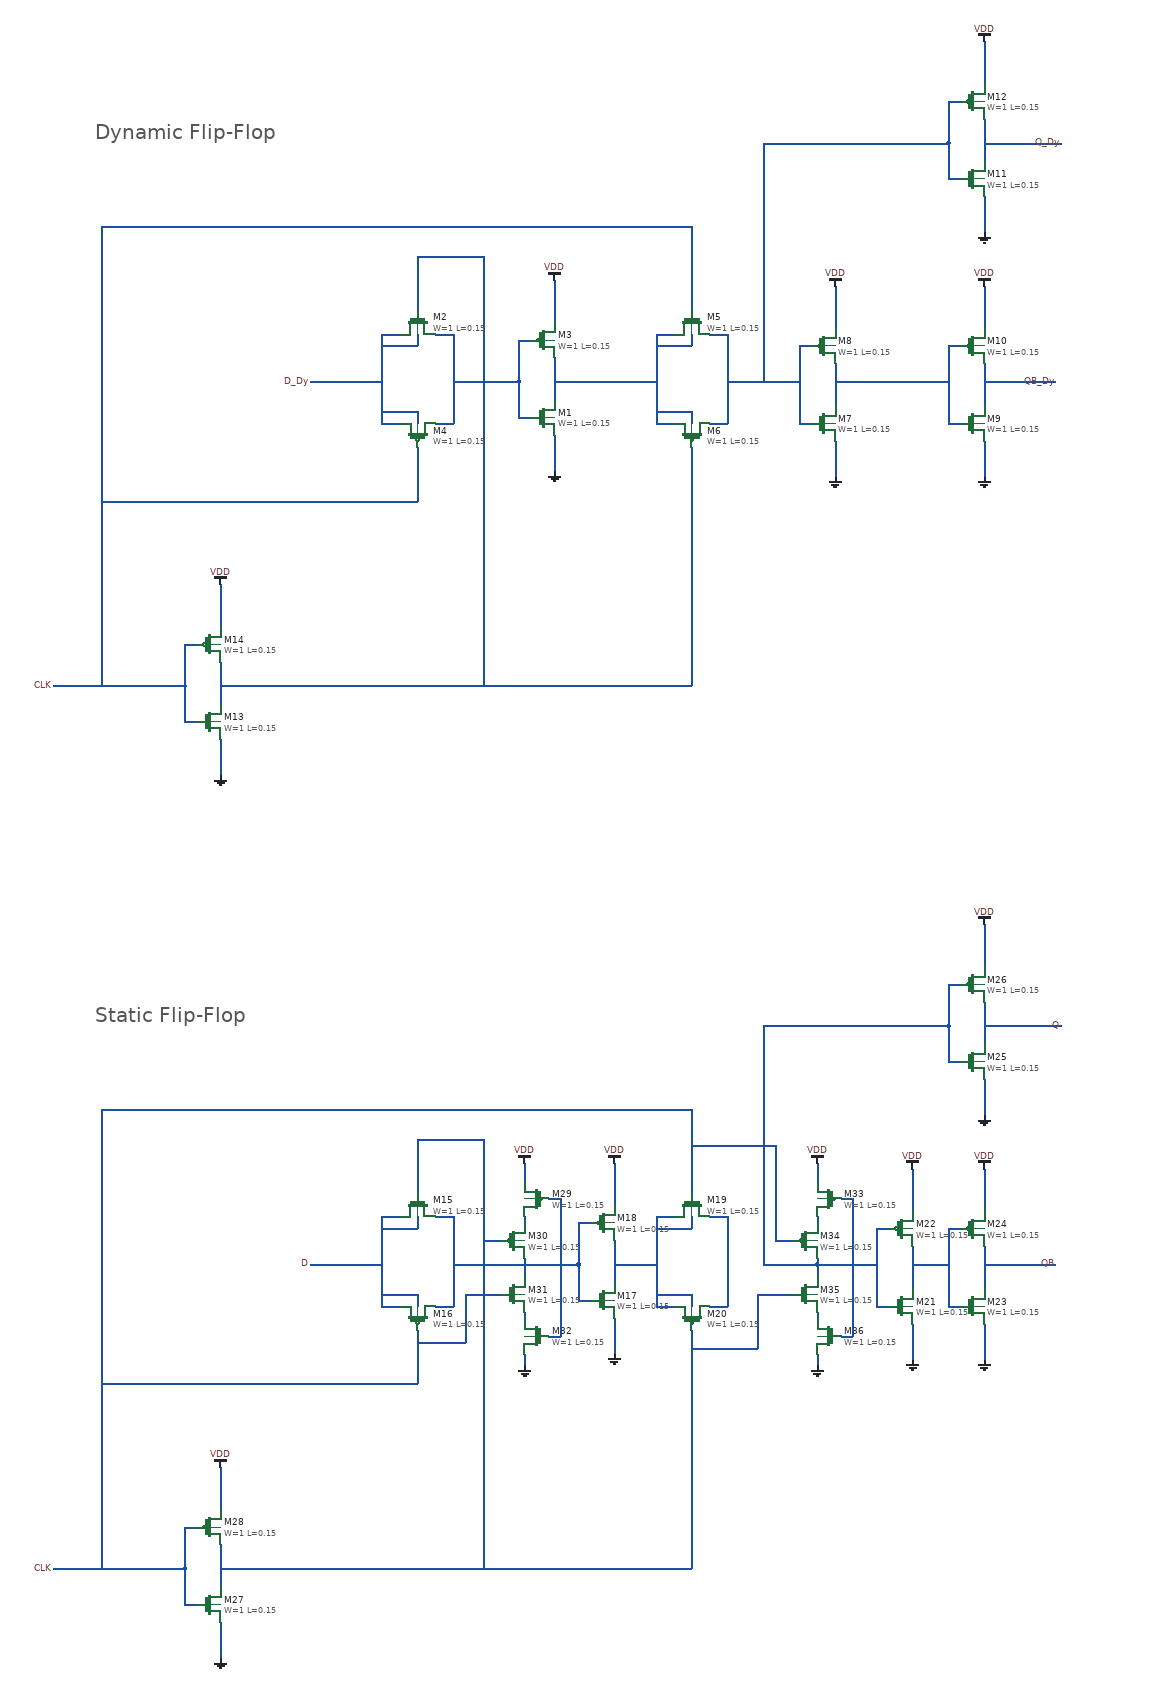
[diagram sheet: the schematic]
v {xschem version=3.4.5 file_version=1.2
}
G {}
K {}
V {}
S {}
E {}
T {Dynamic Flip-Flop
} -1080 -430 0 0 1 1 {}
T {Static Flip-Flop
} -1080 1050 0 0 1 1 {}
N -600 -80 -570 -80 {
lab=D_Dy}
N -600 70 -570 70 {
lab=D_Dy}
N -600 -80 -600 70 {
lab=D_Dy}
N -510 -80 -480 -80 {
lab=#net1}
N -480 -80 -480 70 {
lab=#net1}
N -510 70 -480 70 {
lab=#net1}
N -480 -0 -370 0 {
lab=#net1}
N -540 -80 -540 -60 {
lab=D_Dy}
N -600 -60 -540 -60 {
lab=D_Dy}
N -540 50 -540 70 {
lab=D_Dy}
N -600 50 -540 50 {
lab=D_Dy}
N -310 -40 -310 30 {
lab=#net2}
N -370 -70 -370 0 {
lab=#net1}
N -370 -70 -350 -70 {
lab=#net1}
N -370 -0 -370 60 {
lab=#net1}
N -370 60 -350 60 {
lab=#net1}
N -310 90 -310 150 {
lab=GND}
N -310 -170 -310 -100 {
lab=VDD}
N -140 -80 -110 -80 {
lab=#net2}
N -140 70 -110 70 {
lab=#net2}
N -140 -80 -140 70 {
lab=#net2}
N -50 -80 -20 -80 {
lab=#net3}
N -20 -80 -20 70 {
lab=#net3}
N -50 70 -20 70 {
lab=#net3}
N -80 -80 -80 -60 {
lab=#net2}
N -140 -60 -80 -60 {
lab=#net2}
N -80 50 -80 70 {
lab=#net2}
N -140 50 -80 50 {
lab=#net2}
N -310 0 -140 0 {
lab=#net2}
N 160 -30 160 40 {
lab=#net4}
N 100 -60 100 10 {
lab=#net3}
N 100 -60 120 -60 {
lab=#net3}
N 100 10 100 70 {
lab=#net3}
N 100 70 120 70 {
lab=#net3}
N 160 100 160 160 {
lab=GND}
N 160 -160 160 -90 {
lab=VDD}
N -20 0 100 -0 {
lab=#net3}
N 410 -30 410 40 {
lab=QB_Dy}
N 350 -60 350 10 {
lab=#net4}
N 350 -60 370 -60 {
lab=#net4}
N 350 10 350 70 {
lab=#net4}
N 350 70 370 70 {
lab=#net4}
N 410 100 410 160 {
lab=GND}
N 410 -160 410 -90 {
lab=VDD}
N 410 -440 410 -370 {
lab=Q_Dy}
N 350 -470 350 -400 {
lab=#net3}
N 350 -470 370 -470 {
lab=#net3}
N 350 -400 350 -340 {
lab=#net3}
N 350 -340 370 -340 {
lab=#net3}
N 410 -310 410 -250 {
lab=GND}
N 410 -570 410 -500 {
lab=VDD}
N 160 0 350 0 {
lab=#net4}
N 40 -400 350 -400 {
lab=#net3}
N 40 -400 40 0 {
lab=#net3}
N 410 -400 540 -400 {
lab=Q_Dy}
N 410 0 530 -0 {
lab=QB_Dy}
N -870 470 -870 540 {
lab=#net5}
N -930 440 -930 510 {
lab=CLK}
N -930 440 -910 440 {
lab=CLK}
N -930 510 -930 570 {
lab=CLK}
N -930 570 -910 570 {
lab=CLK}
N -870 600 -870 660 {
lab=GND}
N -870 340 -870 410 {
lab=VDD}
N -720 0 -600 0 {
lab=D_Dy}
N -1150 510 -930 510 {
lab=CLK}
N -1070 -120 -1070 510 {
lab=CLK}
N -540 110 -540 200 {
lab=CLK}
N -1070 200 -540 200 {
lab=CLK}
N -1070 -260 -1070 -120 {
lab=CLK}
N -1070 -260 -80 -260 {
lab=CLK}
N -80 -260 -80 -120 {
lab=CLK}
N -870 510 -90 510 {
lab=#net5}
N -80 110 -80 510 {
lab=#net5}
N -90 510 -80 510 {
lab=#net5}
N -540 -210 -540 -120 {
lab=#net5}
N -540 -210 -430 -210 {
lab=#net5}
N -430 -210 -430 510 {
lab=#net5}
N -600 1400 -570 1400 {
lab=D_Dy}
N -600 1550 -570 1550 {
lab=D_Dy}
N -600 1400 -600 1550 {
lab=D_Dy}
N -510 1400 -480 1400 {
lab=#net6}
N -480 1400 -480 1550 {
lab=#net6}
N -510 1550 -480 1550 {
lab=#net6}
N -480 1480 -270 1480 {
lab=#net6}
N -540 1400 -540 1420 {
lab=D_Dy}
N -600 1420 -540 1420 {
lab=D_Dy}
N -540 1530 -540 1550 {
lab=D_Dy}
N -600 1530 -540 1530 {
lab=D_Dy}
N -210 1440 -210 1510 {
lab=#net7}
N -270 1410 -270 1480 {
lab=#net6}
N -270 1410 -250 1410 {
lab=#net6}
N -270 1480 -270 1540 {
lab=#net6}
N -270 1540 -250 1540 {
lab=#net6}
N -210 1570 -210 1630 {
lab=GND}
N -210 1310 -210 1380 {
lab=VDD}
N -50 1400 -20 1400 {
lab=#net8}
N -20 1400 -20 1550 {
lab=#net8}
N -50 1550 -20 1550 {
lab=#net8}
N -80 1400 -80 1420 {
lab=#net7}
N -80 1530 -80 1550 {
lab=#net7}
N 290 1450 290 1520 {
lab=#net9}
N 230 1420 230 1490 {
lab=#net10}
N 230 1420 250 1420 {
lab=#net10}
N 230 1490 230 1550 {
lab=#net10}
N 230 1550 250 1550 {
lab=#net10}
N 290 1580 290 1640 {
lab=GND}
N 290 1320 290 1390 {
lab=VDD}
N 410 1450 410 1520 {
lab=QB}
N 350 1420 350 1490 {
lab=#net9}
N 350 1420 370 1420 {
lab=#net9}
N 350 1490 350 1550 {
lab=#net9}
N 350 1550 370 1550 {
lab=#net9}
N 410 1580 410 1640 {
lab=GND}
N 410 1320 410 1390 {
lab=VDD}
N 410 1040 410 1110 {
lab=Q}
N 350 1010 350 1080 {
lab=#net10}
N 350 1010 370 1010 {
lab=#net10}
N 350 1080 350 1140 {
lab=#net10}
N 350 1140 370 1140 {
lab=#net10}
N 410 1170 410 1230 {
lab=GND}
N 410 910 410 980 {
lab=VDD}
N 290 1480 350 1480 {
lab=#net9}
N 40 1080 350 1080 {
lab=#net10}
N 40 1080 40 1480 {
lab=#net10}
N 410 1080 540 1080 {
lab=Q}
N 410 1480 530 1480 {
lab=QB}
N -870 1950 -870 2020 {
lab=#net11}
N -930 1920 -930 1990 {
lab=CLK}
N -930 1920 -910 1920 {
lab=CLK}
N -930 1990 -930 2050 {
lab=CLK}
N -930 2050 -910 2050 {
lab=CLK}
N -870 2080 -870 2140 {
lab=GND}
N -870 1820 -870 1890 {
lab=VDD}
N -720 1480 -600 1480 {
lab=D_Dy}
N -1150 1990 -930 1990 {
lab=CLK}
N -1070 1360 -1070 1990 {
lab=CLK}
N -540 1590 -540 1680 {
lab=CLK}
N -1070 1680 -540 1680 {
lab=CLK}
N -1070 1220 -1070 1360 {
lab=CLK}
N -1070 1220 -80 1220 {
lab=CLK}
N -80 1220 -80 1360 {
lab=CLK}
N -870 1990 -90 1990 {
lab=#net11}
N -80 1590 -80 1990 {
lab=#net11}
N -90 1990 -80 1990 {
lab=#net11}
N -540 1270 -540 1360 {
lab=#net11}
N -540 1270 -430 1270 {
lab=#net11}
N -430 1270 -430 1990 {
lab=#net11}
N -140 1400 -110 1400 {
lab=#net7}
N -140 1400 -140 1550 {
lab=#net7}
N -140 1550 -110 1550 {
lab=#net7}
N -140 1420 -80 1420 {
lab=#net7}
N -140 1530 -80 1530 {
lab=#net7}
N -210 1480 -140 1480 {
lab=#net7}
N -360 1400 -360 1410 {
lab=#net12}
N -360 1560 -360 1570 {
lab=#net13}
N -360 1630 -360 1650 {
lab=GND}
N -360 1310 -360 1340 {
lab=VDD}
N -360 1470 -360 1480 {
lab=#net6}
N -360 1480 -360 1500 {
lab=#net6}
N -430 1440 -400 1440 {
lab=#net11}
N -320 1370 -300 1370 {
lab=#net14}
N -300 1370 -300 1600 {
lab=#net14}
N -320 1600 -300 1600 {
lab=#net14}
N -540 1610 -460 1610 {
lab=CLK}
N -460 1530 -460 1610 {
lab=CLK}
N -460 1530 -400 1530 {
lab=CLK}
N 130 1400 130 1410 {
lab=#net15}
N 130 1560 130 1570 {
lab=#net16}
N 130 1630 130 1650 {
lab=GND}
N 130 1310 130 1340 {
lab=VDD}
N 130 1470 130 1480 {
lab=#net10}
N 60 1440 90 1440 {
lab=CLK}
N 170 1370 190 1370 {
lab=#net17}
N 190 1370 190 1600 {
lab=#net17}
N 170 1600 190 1600 {
lab=#net17}
N 30 1530 90 1530 {
lab=#net11}
N 30 1530 30 1620 {
lab=#net11}
N -80 1620 30 1620 {
lab=#net11}
N 60 1280 60 1440 {
lab=CLK}
N -80 1280 60 1280 {
lab=CLK}
N 130 1480 130 1500 {
lab=#net10}
N 40 1480 130 1480 {
lab=#net10}
N 130 1480 230 1480 {
lab=#net10}
C {sky130_fd_pr/nfet_01v8.sym} -540 -100 1 0 {name=M2
L=0.15
W=1
nf=1 
mult=1
ad="'int((nf+1)/2) * W/nf * 0.29'" 
pd="'2*int((nf+1)/2) * (W/nf + 0.29)'"
as="'int((nf+2)/2) * W/nf * 0.29'" 
ps="'2*int((nf+2)/2) * (W/nf + 0.29)'"
nrd="'0.29 / W'" nrs="'0.29 / W'"
sa=0 sb=0 sd=0
model=nfet_01v8
spiceprefix=X
}
C {sky130_fd_pr/pfet_01v8.sym} -540 90 3 0 {name=M4
L=0.15
W=1
nf=1
mult=1
ad="'int((nf+1)/2) * W/nf * 0.29'" 
pd="'2*int((nf+1)/2) * (W/nf + 0.29)'"
as="'int((nf+2)/2) * W/nf * 0.29'" 
ps="'2*int((nf+2)/2) * (W/nf + 0.29)'"
nrd="'0.29 / W'" nrs="'0.29 / W'"
sa=0 sb=0 sd=0
model=pfet_01v8
spiceprefix=X
}
C {sky130_fd_pr/nfet_01v8.sym} -330 60 0 0 {name=M1
L=0.15
W=1
nf=1 
mult=1
ad="'int((nf+1)/2) * W/nf * 0.29'" 
pd="'2*int((nf+1)/2) * (W/nf + 0.29)'"
as="'int((nf+2)/2) * W/nf * 0.29'" 
ps="'2*int((nf+2)/2) * (W/nf + 0.29)'"
nrd="'0.29 / W'" nrs="'0.29 / W'"
sa=0 sb=0 sd=0
model=nfet_01v8
spiceprefix=X
}
C {sky130_fd_pr/pfet_01v8.sym} -330 -70 0 0 {name=M3
L=0.15
W=1
nf=1
mult=1
ad="'int((nf+1)/2) * W/nf * 0.29'" 
pd="'2*int((nf+1)/2) * (W/nf + 0.29)'"
as="'int((nf+2)/2) * W/nf * 0.29'" 
ps="'2*int((nf+2)/2) * (W/nf + 0.29)'"
nrd="'0.29 / W'" nrs="'0.29 / W'"
sa=0 sb=0 sd=0
model=pfet_01v8
spiceprefix=X
}
C {sky130_fd_pr/nfet_01v8.sym} -80 -100 1 0 {name=M5
L=0.15
W=1
nf=1 
mult=1
ad="'int((nf+1)/2) * W/nf * 0.29'" 
pd="'2*int((nf+1)/2) * (W/nf + 0.29)'"
as="'int((nf+2)/2) * W/nf * 0.29'" 
ps="'2*int((nf+2)/2) * (W/nf + 0.29)'"
nrd="'0.29 / W'" nrs="'0.29 / W'"
sa=0 sb=0 sd=0
model=nfet_01v8
spiceprefix=X
}
C {sky130_fd_pr/pfet_01v8.sym} -80 90 3 0 {name=M6
L=0.15
W=1
nf=1
mult=1
ad="'int((nf+1)/2) * W/nf * 0.29'" 
pd="'2*int((nf+1)/2) * (W/nf + 0.29)'"
as="'int((nf+2)/2) * W/nf * 0.29'" 
ps="'2*int((nf+2)/2) * (W/nf + 0.29)'"
nrd="'0.29 / W'" nrs="'0.29 / W'"
sa=0 sb=0 sd=0
model=pfet_01v8
spiceprefix=X
}
C {sky130_fd_pr/nfet_01v8.sym} 140 70 0 0 {name=M7
L=0.15
W=1
nf=1 
mult=1
ad="'int((nf+1)/2) * W/nf * 0.29'" 
pd="'2*int((nf+1)/2) * (W/nf + 0.29)'"
as="'int((nf+2)/2) * W/nf * 0.29'" 
ps="'2*int((nf+2)/2) * (W/nf + 0.29)'"
nrd="'0.29 / W'" nrs="'0.29 / W'"
sa=0 sb=0 sd=0
model=nfet_01v8
spiceprefix=X
}
C {sky130_fd_pr/pfet_01v8.sym} 140 -60 0 0 {name=M8
L=0.15
W=1
nf=1
mult=1
ad="'int((nf+1)/2) * W/nf * 0.29'" 
pd="'2*int((nf+1)/2) * (W/nf + 0.29)'"
as="'int((nf+2)/2) * W/nf * 0.29'" 
ps="'2*int((nf+2)/2) * (W/nf + 0.29)'"
nrd="'0.29 / W'" nrs="'0.29 / W'"
sa=0 sb=0 sd=0
model=pfet_01v8
spiceprefix=X
}
C {devices/gnd.sym} -310 150 0 0 {name=l1 lab=GND}
C {devices/gnd.sym} 160 160 0 0 {name=l2 lab=GND}
C {sky130_fd_pr/nfet_01v8.sym} 390 70 0 0 {name=M9
L=0.15
W=1
nf=1 
mult=1
ad="'int((nf+1)/2) * W/nf * 0.29'" 
pd="'2*int((nf+1)/2) * (W/nf + 0.29)'"
as="'int((nf+2)/2) * W/nf * 0.29'" 
ps="'2*int((nf+2)/2) * (W/nf + 0.29)'"
nrd="'0.29 / W'" nrs="'0.29 / W'"
sa=0 sb=0 sd=0
model=nfet_01v8
spiceprefix=X
}
C {sky130_fd_pr/pfet_01v8.sym} 390 -60 0 0 {name=M10
L=0.15
W=1
nf=1
mult=1
ad="'int((nf+1)/2) * W/nf * 0.29'" 
pd="'2*int((nf+1)/2) * (W/nf + 0.29)'"
as="'int((nf+2)/2) * W/nf * 0.29'" 
ps="'2*int((nf+2)/2) * (W/nf + 0.29)'"
nrd="'0.29 / W'" nrs="'0.29 / W'"
sa=0 sb=0 sd=0
model=pfet_01v8
spiceprefix=X
}
C {devices/gnd.sym} 410 160 0 0 {name=l3 lab=GND}
C {sky130_fd_pr/nfet_01v8.sym} 390 -340 0 0 {name=M11
L=0.15
W=1
nf=1 
mult=1
ad="'int((nf+1)/2) * W/nf * 0.29'" 
pd="'2*int((nf+1)/2) * (W/nf + 0.29)'"
as="'int((nf+2)/2) * W/nf * 0.29'" 
ps="'2*int((nf+2)/2) * (W/nf + 0.29)'"
nrd="'0.29 / W'" nrs="'0.29 / W'"
sa=0 sb=0 sd=0
model=nfet_01v8
spiceprefix=X
}
C {sky130_fd_pr/pfet_01v8.sym} 390 -470 0 0 {name=M12
L=0.15
W=1
nf=1
mult=1
ad="'int((nf+1)/2) * W/nf * 0.29'" 
pd="'2*int((nf+1)/2) * (W/nf + 0.29)'"
as="'int((nf+2)/2) * W/nf * 0.29'" 
ps="'2*int((nf+2)/2) * (W/nf + 0.29)'"
nrd="'0.29 / W'" nrs="'0.29 / W'"
sa=0 sb=0 sd=0
model=pfet_01v8
spiceprefix=X
}
C {devices/gnd.sym} 410 -250 0 0 {name=l4 lab=GND}
C {devices/lab_pin.sym} 540 -400 0 0 {name=p1 sig_type=std_logic lab=Q_Dy

}
C {devices/lab_pin.sym} 530 0 0 0 {name=p2 sig_type=std_logic lab=QB_Dy

}
C {sky130_fd_pr/nfet_01v8.sym} -890 570 0 0 {name=M13
L=0.15
W=1
nf=1 
mult=1
ad="'int((nf+1)/2) * W/nf * 0.29'" 
pd="'2*int((nf+1)/2) * (W/nf + 0.29)'"
as="'int((nf+2)/2) * W/nf * 0.29'" 
ps="'2*int((nf+2)/2) * (W/nf + 0.29)'"
nrd="'0.29 / W'" nrs="'0.29 / W'"
sa=0 sb=0 sd=0
model=nfet_01v8
spiceprefix=X
}
C {sky130_fd_pr/pfet_01v8.sym} -890 440 0 0 {name=M14
L=0.15
W=1
nf=1
mult=1
ad="'int((nf+1)/2) * W/nf * 0.29'" 
pd="'2*int((nf+1)/2) * (W/nf + 0.29)'"
as="'int((nf+2)/2) * W/nf * 0.29'" 
ps="'2*int((nf+2)/2) * (W/nf + 0.29)'"
nrd="'0.29 / W'" nrs="'0.29 / W'"
sa=0 sb=0 sd=0
model=pfet_01v8
spiceprefix=X
}
C {devices/gnd.sym} -870 660 0 0 {name=l5 lab=GND}
C {devices/lab_pin.sym} -720 0 0 0 {name=p3 sig_type=std_logic lab=D_Dy


}
C {devices/vdd.sym} -870 340 0 0 {name=l6 lab=VDD}
C {devices/vdd.sym} -310 -170 0 0 {name=l7 lab=VDD}
C {devices/vdd.sym} 160 -160 0 0 {name=l8 lab=VDD}
C {devices/vdd.sym} 410 -160 0 0 {name=l9 lab=VDD}
C {devices/vdd.sym} 410 -570 0 0 {name=l10 lab=VDD}
C {devices/lab_pin.sym} -1150 510 0 0 {name=p4 sig_type=std_logic lab=CLK



}
C {sky130_fd_pr/nfet_01v8.sym} -540 1380 1 0 {name=M15
L=0.15
W=1
nf=1 
mult=1
ad="'int((nf+1)/2) * W/nf * 0.29'" 
pd="'2*int((nf+1)/2) * (W/nf + 0.29)'"
as="'int((nf+2)/2) * W/nf * 0.29'" 
ps="'2*int((nf+2)/2) * (W/nf + 0.29)'"
nrd="'0.29 / W'" nrs="'0.29 / W'"
sa=0 sb=0 sd=0
model=nfet_01v8
spiceprefix=X
}
C {sky130_fd_pr/pfet_01v8.sym} -540 1570 3 0 {name=M16
L=0.15
W=1
nf=1
mult=1
ad="'int((nf+1)/2) * W/nf * 0.29'" 
pd="'2*int((nf+1)/2) * (W/nf + 0.29)'"
as="'int((nf+2)/2) * W/nf * 0.29'" 
ps="'2*int((nf+2)/2) * (W/nf + 0.29)'"
nrd="'0.29 / W'" nrs="'0.29 / W'"
sa=0 sb=0 sd=0
model=pfet_01v8
spiceprefix=X
}
C {sky130_fd_pr/nfet_01v8.sym} -230 1540 0 0 {name=M17
L=0.15
W=1
nf=1 
mult=1
ad="'int((nf+1)/2) * W/nf * 0.29'" 
pd="'2*int((nf+1)/2) * (W/nf + 0.29)'"
as="'int((nf+2)/2) * W/nf * 0.29'" 
ps="'2*int((nf+2)/2) * (W/nf + 0.29)'"
nrd="'0.29 / W'" nrs="'0.29 / W'"
sa=0 sb=0 sd=0
model=nfet_01v8
spiceprefix=X
}
C {sky130_fd_pr/pfet_01v8.sym} -230 1410 0 0 {name=M18
L=0.15
W=1
nf=1
mult=1
ad="'int((nf+1)/2) * W/nf * 0.29'" 
pd="'2*int((nf+1)/2) * (W/nf + 0.29)'"
as="'int((nf+2)/2) * W/nf * 0.29'" 
ps="'2*int((nf+2)/2) * (W/nf + 0.29)'"
nrd="'0.29 / W'" nrs="'0.29 / W'"
sa=0 sb=0 sd=0
model=pfet_01v8
spiceprefix=X
}
C {sky130_fd_pr/nfet_01v8.sym} -80 1380 1 0 {name=M19
L=0.15
W=1
nf=1 
mult=1
ad="'int((nf+1)/2) * W/nf * 0.29'" 
pd="'2*int((nf+1)/2) * (W/nf + 0.29)'"
as="'int((nf+2)/2) * W/nf * 0.29'" 
ps="'2*int((nf+2)/2) * (W/nf + 0.29)'"
nrd="'0.29 / W'" nrs="'0.29 / W'"
sa=0 sb=0 sd=0
model=nfet_01v8
spiceprefix=X
}
C {sky130_fd_pr/pfet_01v8.sym} -80 1570 3 0 {name=M20
L=0.15
W=1
nf=1
mult=1
ad="'int((nf+1)/2) * W/nf * 0.29'" 
pd="'2*int((nf+1)/2) * (W/nf + 0.29)'"
as="'int((nf+2)/2) * W/nf * 0.29'" 
ps="'2*int((nf+2)/2) * (W/nf + 0.29)'"
nrd="'0.29 / W'" nrs="'0.29 / W'"
sa=0 sb=0 sd=0
model=pfet_01v8
spiceprefix=X
}
C {sky130_fd_pr/nfet_01v8.sym} 270 1550 0 0 {name=M21
L=0.15
W=1
nf=1 
mult=1
ad="'int((nf+1)/2) * W/nf * 0.29'" 
pd="'2*int((nf+1)/2) * (W/nf + 0.29)'"
as="'int((nf+2)/2) * W/nf * 0.29'" 
ps="'2*int((nf+2)/2) * (W/nf + 0.29)'"
nrd="'0.29 / W'" nrs="'0.29 / W'"
sa=0 sb=0 sd=0
model=nfet_01v8
spiceprefix=X
}
C {sky130_fd_pr/pfet_01v8.sym} 270 1420 0 0 {name=M22
L=0.15
W=1
nf=1
mult=1
ad="'int((nf+1)/2) * W/nf * 0.29'" 
pd="'2*int((nf+1)/2) * (W/nf + 0.29)'"
as="'int((nf+2)/2) * W/nf * 0.29'" 
ps="'2*int((nf+2)/2) * (W/nf + 0.29)'"
nrd="'0.29 / W'" nrs="'0.29 / W'"
sa=0 sb=0 sd=0
model=pfet_01v8
spiceprefix=X
}
C {devices/gnd.sym} -210 1630 0 0 {name=l11 lab=GND}
C {devices/gnd.sym} 290 1640 0 0 {name=l12 lab=GND}
C {sky130_fd_pr/nfet_01v8.sym} 390 1550 0 0 {name=M23
L=0.15
W=1
nf=1 
mult=1
ad="'int((nf+1)/2) * W/nf * 0.29'" 
pd="'2*int((nf+1)/2) * (W/nf + 0.29)'"
as="'int((nf+2)/2) * W/nf * 0.29'" 
ps="'2*int((nf+2)/2) * (W/nf + 0.29)'"
nrd="'0.29 / W'" nrs="'0.29 / W'"
sa=0 sb=0 sd=0
model=nfet_01v8
spiceprefix=X
}
C {sky130_fd_pr/pfet_01v8.sym} 390 1420 0 0 {name=M24
L=0.15
W=1
nf=1
mult=1
ad="'int((nf+1)/2) * W/nf * 0.29'" 
pd="'2*int((nf+1)/2) * (W/nf + 0.29)'"
as="'int((nf+2)/2) * W/nf * 0.29'" 
ps="'2*int((nf+2)/2) * (W/nf + 0.29)'"
nrd="'0.29 / W'" nrs="'0.29 / W'"
sa=0 sb=0 sd=0
model=pfet_01v8
spiceprefix=X
}
C {devices/gnd.sym} 410 1640 0 0 {name=l13 lab=GND}
C {sky130_fd_pr/nfet_01v8.sym} 390 1140 0 0 {name=M25
L=0.15
W=1
nf=1 
mult=1
ad="'int((nf+1)/2) * W/nf * 0.29'" 
pd="'2*int((nf+1)/2) * (W/nf + 0.29)'"
as="'int((nf+2)/2) * W/nf * 0.29'" 
ps="'2*int((nf+2)/2) * (W/nf + 0.29)'"
nrd="'0.29 / W'" nrs="'0.29 / W'"
sa=0 sb=0 sd=0
model=nfet_01v8
spiceprefix=X
}
C {sky130_fd_pr/pfet_01v8.sym} 390 1010 0 0 {name=M26
L=0.15
W=1
nf=1
mult=1
ad="'int((nf+1)/2) * W/nf * 0.29'" 
pd="'2*int((nf+1)/2) * (W/nf + 0.29)'"
as="'int((nf+2)/2) * W/nf * 0.29'" 
ps="'2*int((nf+2)/2) * (W/nf + 0.29)'"
nrd="'0.29 / W'" nrs="'0.29 / W'"
sa=0 sb=0 sd=0
model=pfet_01v8
spiceprefix=X
}
C {devices/gnd.sym} 410 1230 0 0 {name=l14 lab=GND}
C {devices/lab_pin.sym} 540 1080 0 0 {name=p5 sig_type=std_logic lab=Q


}
C {devices/lab_pin.sym} 530 1480 0 0 {name=p6 sig_type=std_logic lab=QB


}
C {sky130_fd_pr/nfet_01v8.sym} -890 2050 0 0 {name=M27
L=0.15
W=1
nf=1 
mult=1
ad="'int((nf+1)/2) * W/nf * 0.29'" 
pd="'2*int((nf+1)/2) * (W/nf + 0.29)'"
as="'int((nf+2)/2) * W/nf * 0.29'" 
ps="'2*int((nf+2)/2) * (W/nf + 0.29)'"
nrd="'0.29 / W'" nrs="'0.29 / W'"
sa=0 sb=0 sd=0
model=nfet_01v8
spiceprefix=X
}
C {sky130_fd_pr/pfet_01v8.sym} -890 1920 0 0 {name=M28
L=0.15
W=1
nf=1
mult=1
ad="'int((nf+1)/2) * W/nf * 0.29'" 
pd="'2*int((nf+1)/2) * (W/nf + 0.29)'"
as="'int((nf+2)/2) * W/nf * 0.29'" 
ps="'2*int((nf+2)/2) * (W/nf + 0.29)'"
nrd="'0.29 / W'" nrs="'0.29 / W'"
sa=0 sb=0 sd=0
model=pfet_01v8
spiceprefix=X
}
C {devices/gnd.sym} -870 2140 0 0 {name=l15 lab=GND}
C {devices/lab_pin.sym} -720 1480 0 0 {name=p7 sig_type=std_logic lab=D



}
C {devices/vdd.sym} -870 1820 0 0 {name=l16 lab=VDD}
C {devices/vdd.sym} -210 1310 0 0 {name=l17 lab=VDD}
C {devices/vdd.sym} 290 1320 0 0 {name=l18 lab=VDD}
C {devices/vdd.sym} 410 1320 0 0 {name=l19 lab=VDD}
C {devices/vdd.sym} 410 910 0 0 {name=l20 lab=VDD}
C {devices/lab_pin.sym} -1150 1990 0 0 {name=p8 sig_type=std_logic lab=CLK



}
C {sky130_fd_pr/pfet_01v8.sym} -340 1370 0 1 {name=M29
L=0.15
W=1
nf=1
mult=1
ad="'int((nf+1)/2) * W/nf * 0.29'" 
pd="'2*int((nf+1)/2) * (W/nf + 0.29)'"
as="'int((nf+2)/2) * W/nf * 0.29'" 
ps="'2*int((nf+2)/2) * (W/nf + 0.29)'"
nrd="'0.29 / W'" nrs="'0.29 / W'"
sa=0 sb=0 sd=0
model=pfet_01v8
spiceprefix=X
}
C {sky130_fd_pr/pfet_01v8.sym} -380 1440 0 0 {name=M30
L=0.15
W=1
nf=1
mult=1
ad="'int((nf+1)/2) * W/nf * 0.29'" 
pd="'2*int((nf+1)/2) * (W/nf + 0.29)'"
as="'int((nf+2)/2) * W/nf * 0.29'" 
ps="'2*int((nf+2)/2) * (W/nf + 0.29)'"
nrd="'0.29 / W'" nrs="'0.29 / W'"
sa=0 sb=0 sd=0
model=pfet_01v8
spiceprefix=X
}
C {sky130_fd_pr/nfet_01v8.sym} -380 1530 0 0 {name=M31
L=0.15
W=1
nf=1 
mult=1
ad="'int((nf+1)/2) * W/nf * 0.29'" 
pd="'2*int((nf+1)/2) * (W/nf + 0.29)'"
as="'int((nf+2)/2) * W/nf * 0.29'" 
ps="'2*int((nf+2)/2) * (W/nf + 0.29)'"
nrd="'0.29 / W'" nrs="'0.29 / W'"
sa=0 sb=0 sd=0
model=nfet_01v8
spiceprefix=X
}
C {sky130_fd_pr/nfet_01v8.sym} -340 1600 0 1 {name=M32
L=0.15
W=1
nf=1 
mult=1
ad="'int((nf+1)/2) * W/nf * 0.29'" 
pd="'2*int((nf+1)/2) * (W/nf + 0.29)'"
as="'int((nf+2)/2) * W/nf * 0.29'" 
ps="'2*int((nf+2)/2) * (W/nf + 0.29)'"
nrd="'0.29 / W'" nrs="'0.29 / W'"
sa=0 sb=0 sd=0
model=nfet_01v8
spiceprefix=X
}
C {devices/gnd.sym} -360 1650 0 0 {name=l21 lab=GND}
C {devices/vdd.sym} -360 1310 0 0 {name=l22 lab=VDD}
C {sky130_fd_pr/pfet_01v8.sym} 150 1370 0 1 {name=M33
L=0.15
W=1
nf=1
mult=1
ad="'int((nf+1)/2) * W/nf * 0.29'" 
pd="'2*int((nf+1)/2) * (W/nf + 0.29)'"
as="'int((nf+2)/2) * W/nf * 0.29'" 
ps="'2*int((nf+2)/2) * (W/nf + 0.29)'"
nrd="'0.29 / W'" nrs="'0.29 / W'"
sa=0 sb=0 sd=0
model=pfet_01v8
spiceprefix=X
}
C {sky130_fd_pr/pfet_01v8.sym} 110 1440 0 0 {name=M34
L=0.15
W=1
nf=1
mult=1
ad="'int((nf+1)/2) * W/nf * 0.29'" 
pd="'2*int((nf+1)/2) * (W/nf + 0.29)'"
as="'int((nf+2)/2) * W/nf * 0.29'" 
ps="'2*int((nf+2)/2) * (W/nf + 0.29)'"
nrd="'0.29 / W'" nrs="'0.29 / W'"
sa=0 sb=0 sd=0
model=pfet_01v8
spiceprefix=X
}
C {sky130_fd_pr/nfet_01v8.sym} 110 1530 0 0 {name=M35
L=0.15
W=1
nf=1 
mult=1
ad="'int((nf+1)/2) * W/nf * 0.29'" 
pd="'2*int((nf+1)/2) * (W/nf + 0.29)'"
as="'int((nf+2)/2) * W/nf * 0.29'" 
ps="'2*int((nf+2)/2) * (W/nf + 0.29)'"
nrd="'0.29 / W'" nrs="'0.29 / W'"
sa=0 sb=0 sd=0
model=nfet_01v8
spiceprefix=X
}
C {sky130_fd_pr/nfet_01v8.sym} 150 1600 0 1 {name=M36
L=0.15
W=1
nf=1 
mult=1
ad="'int((nf+1)/2) * W/nf * 0.29'" 
pd="'2*int((nf+1)/2) * (W/nf + 0.29)'"
as="'int((nf+2)/2) * W/nf * 0.29'" 
ps="'2*int((nf+2)/2) * (W/nf + 0.29)'"
nrd="'0.29 / W'" nrs="'0.29 / W'"
sa=0 sb=0 sd=0
model=nfet_01v8
spiceprefix=X
}
C {devices/gnd.sym} 130 1650 0 0 {name=l23 lab=GND}
C {devices/vdd.sym} 130 1310 0 0 {name=l24 lab=VDD}
